VERSION 5.8 ;
BUSBITCHARS "[]" ;
DIVIDERCHAR "/" ;
UNITS
    DATABASE MICRONS 1000 ;
END UNITS

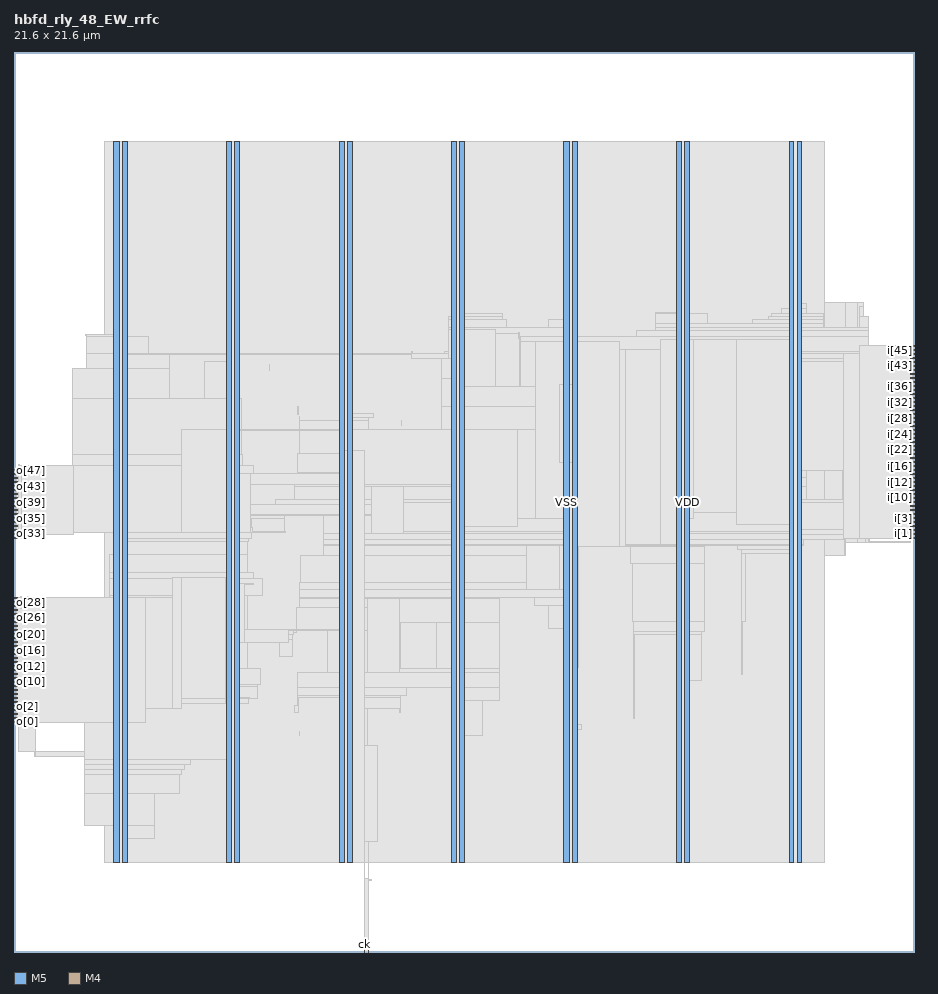
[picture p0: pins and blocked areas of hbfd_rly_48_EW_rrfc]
MACRO hbfd_rly_48_EW_rrfc
  FOREIGN hbfd_rly_48_EW_rrfc 0 0 ;
  CLASS BLOCK ;
  SIZE 21.6 BY 21.6 ;
  PIN ck
    DIRECTION INPUT ;
    USE SIGNAL ;
    PORT
      LAYER M5 ;
        RECT  8.4 0 8.424 0.084 ;
    END
  END ck
  PIN i[0]
    DIRECTION INPUT ;
    USE SIGNAL ;
    PORT
      LAYER M4 ;
        RECT  21.516 9.936 21.6 9.96 ;
    END
  END i[0]
  PIN i[10]
    DIRECTION INPUT ;
    USE SIGNAL ;
    PORT
      LAYER M4 ;
        RECT  21.516 10.896 21.6 10.92 ;
    END
  END i[10]
  PIN i[11]
    DIRECTION INPUT ;
    USE SIGNAL ;
    PORT
      LAYER M4 ;
        RECT  21.516 10.992 21.6 11.016 ;
    END
  END i[11]
  PIN i[12]
    DIRECTION INPUT ;
    USE SIGNAL ;
    PORT
      LAYER M4 ;
        RECT  21.516 11.088 21.6 11.112 ;
    END
  END i[12]
  PIN i[13]
    DIRECTION INPUT ;
    USE SIGNAL ;
    PORT
      LAYER M4 ;
        RECT  21.516 11.184 21.6 11.208 ;
    END
  END i[13]
  PIN i[14]
    DIRECTION INPUT ;
    USE SIGNAL ;
    PORT
      LAYER M4 ;
        RECT  21.516 11.28 21.6 11.304 ;
    END
  END i[14]
  PIN i[15]
    DIRECTION INPUT ;
    USE SIGNAL ;
    PORT
      LAYER M4 ;
        RECT  21.516 11.376 21.6 11.4 ;
    END
  END i[15]
  PIN i[16]
    DIRECTION INPUT ;
    USE SIGNAL ;
    PORT
      LAYER M4 ;
        RECT  21.516 11.472 21.6 11.496 ;
    END
  END i[16]
  PIN i[17]
    DIRECTION INPUT ;
    USE SIGNAL ;
    PORT
      LAYER M4 ;
        RECT  21.516 11.568 21.6 11.592 ;
    END
  END i[17]
  PIN i[18]
    DIRECTION INPUT ;
    USE SIGNAL ;
    PORT
      LAYER M4 ;
        RECT  21.516 11.664 21.6 11.688 ;
    END
  END i[18]
  PIN i[19]
    DIRECTION INPUT ;
    USE SIGNAL ;
    PORT
      LAYER M4 ;
        RECT  21.516 11.76 21.6 11.784 ;
    END
  END i[19]
  PIN i[1]
    DIRECTION INPUT ;
    USE SIGNAL ;
    PORT
      LAYER M4 ;
        RECT  21.516 10.032 21.6 10.056 ;
    END
  END i[1]
  PIN i[20]
    DIRECTION INPUT ;
    USE SIGNAL ;
    PORT
      LAYER M4 ;
        RECT  21.516 11.856 21.6 11.88 ;
    END
  END i[20]
  PIN i[21]
    DIRECTION INPUT ;
    USE SIGNAL ;
    PORT
      LAYER M4 ;
        RECT  21.516 11.952 21.6 11.976 ;
    END
  END i[21]
  PIN i[22]
    DIRECTION INPUT ;
    USE SIGNAL ;
    PORT
      LAYER M4 ;
        RECT  21.516 12.048 21.6 12.072 ;
    END
  END i[22]
  PIN i[23]
    DIRECTION INPUT ;
    USE SIGNAL ;
    PORT
      LAYER M4 ;
        RECT  21.516 12.144 21.6 12.168 ;
    END
  END i[23]
  PIN i[24]
    DIRECTION INPUT ;
    USE SIGNAL ;
    PORT
      LAYER M4 ;
        RECT  21.516 12.24 21.6 12.264 ;
    END
  END i[24]
  PIN i[25]
    DIRECTION INPUT ;
    USE SIGNAL ;
    PORT
      LAYER M4 ;
        RECT  21.516 12.336 21.6 12.36 ;
    END
  END i[25]
  PIN i[26]
    DIRECTION INPUT ;
    USE SIGNAL ;
    PORT
      LAYER M4 ;
        RECT  21.516 12.432 21.6 12.456 ;
    END
  END i[26]
  PIN i[27]
    DIRECTION INPUT ;
    USE SIGNAL ;
    PORT
      LAYER M4 ;
        RECT  21.516 12.528 21.6 12.552 ;
    END
  END i[27]
  PIN i[28]
    DIRECTION INPUT ;
    USE SIGNAL ;
    PORT
      LAYER M4 ;
        RECT  21.516 12.624 21.6 12.648 ;
    END
  END i[28]
  PIN i[29]
    DIRECTION INPUT ;
    USE SIGNAL ;
    PORT
      LAYER M4 ;
        RECT  21.516 12.72 21.6 12.744 ;
    END
  END i[29]
  PIN i[2]
    DIRECTION INPUT ;
    USE SIGNAL ;
    PORT
      LAYER M4 ;
        RECT  21.516 10.128 21.6 10.152 ;
    END
  END i[2]
  PIN i[30]
    DIRECTION INPUT ;
    USE SIGNAL ;
    PORT
      LAYER M4 ;
        RECT  21.516 12.816 21.6 12.84 ;
    END
  END i[30]
  PIN i[31]
    DIRECTION INPUT ;
    USE SIGNAL ;
    PORT
      LAYER M4 ;
        RECT  21.516 12.912 21.6 12.936 ;
    END
  END i[31]
  PIN i[32]
    DIRECTION INPUT ;
    USE SIGNAL ;
    PORT
      LAYER M4 ;
        RECT  21.516 13.008 21.6 13.032 ;
    END
  END i[32]
  PIN i[33]
    DIRECTION INPUT ;
    USE SIGNAL ;
    PORT
      LAYER M4 ;
        RECT  21.516 13.104 21.6 13.128 ;
    END
  END i[33]
  PIN i[34]
    DIRECTION INPUT ;
    USE SIGNAL ;
    PORT
      LAYER M4 ;
        RECT  21.516 13.2 21.6 13.224 ;
    END
  END i[34]
  PIN i[35]
    DIRECTION INPUT ;
    USE SIGNAL ;
    PORT
      LAYER M4 ;
        RECT  21.516 13.296 21.6 13.32 ;
    END
  END i[35]
  PIN i[36]
    DIRECTION INPUT ;
    USE SIGNAL ;
    PORT
      LAYER M4 ;
        RECT  21.516 13.392 21.6 13.416 ;
    END
  END i[36]
  PIN i[37]
    DIRECTION INPUT ;
    USE SIGNAL ;
    PORT
      LAYER M4 ;
        RECT  21.516 13.488 21.6 13.512 ;
    END
  END i[37]
  PIN i[38]
    DIRECTION INPUT ;
    USE SIGNAL ;
    PORT
      LAYER M4 ;
        RECT  21.516 13.584 21.6 13.608 ;
    END
  END i[38]
  PIN i[39]
    DIRECTION INPUT ;
    USE SIGNAL ;
    PORT
      LAYER M4 ;
        RECT  21.516 13.68 21.6 13.704 ;
    END
  END i[39]
  PIN i[3]
    DIRECTION INPUT ;
    USE SIGNAL ;
    PORT
      LAYER M4 ;
        RECT  21.516 10.224 21.6 10.248 ;
    END
  END i[3]
  PIN i[40]
    DIRECTION INPUT ;
    USE SIGNAL ;
    PORT
      LAYER M4 ;
        RECT  21.516 13.776 21.6 13.8 ;
    END
  END i[40]
  PIN i[41]
    DIRECTION INPUT ;
    USE SIGNAL ;
    PORT
      LAYER M4 ;
        RECT  21.516 13.872 21.6 13.896 ;
    END
  END i[41]
  PIN i[42]
    DIRECTION INPUT ;
    USE SIGNAL ;
    PORT
      LAYER M4 ;
        RECT  21.516 13.968 21.6 13.992 ;
    END
  END i[42]
  PIN i[43]
    DIRECTION INPUT ;
    USE SIGNAL ;
    PORT
      LAYER M4 ;
        RECT  21.516 14.064 21.6 14.088 ;
    END
  END i[43]
  PIN i[44]
    DIRECTION INPUT ;
    USE SIGNAL ;
    PORT
      LAYER M4 ;
        RECT  21.516 14.16 21.6 14.184 ;
    END
  END i[44]
  PIN i[45]
    DIRECTION INPUT ;
    USE SIGNAL ;
    PORT
      LAYER M4 ;
        RECT  21.516 14.256 21.6 14.28 ;
    END
  END i[45]
  PIN i[46]
    DIRECTION INPUT ;
    USE SIGNAL ;
    PORT
      LAYER M4 ;
        RECT  21.516 14.352 21.6 14.376 ;
    END
  END i[46]
  PIN i[47]
    DIRECTION INPUT ;
    USE SIGNAL ;
    PORT
      LAYER M4 ;
        RECT  21.516 14.448 21.6 14.472 ;
    END
  END i[47]
  PIN i[4]
    DIRECTION INPUT ;
    USE SIGNAL ;
    PORT
      LAYER M4 ;
        RECT  21.516 10.32 21.6 10.344 ;
    END
  END i[4]
  PIN i[5]
    DIRECTION INPUT ;
    USE SIGNAL ;
    PORT
      LAYER M4 ;
        RECT  21.516 10.416 21.6 10.44 ;
    END
  END i[5]
  PIN i[6]
    DIRECTION INPUT ;
    USE SIGNAL ;
    PORT
      LAYER M4 ;
        RECT  21.516 10.512 21.6 10.536 ;
    END
  END i[6]
  PIN i[7]
    DIRECTION INPUT ;
    USE SIGNAL ;
    PORT
      LAYER M4 ;
        RECT  21.516 10.608 21.6 10.632 ;
    END
  END i[7]
  PIN i[8]
    DIRECTION INPUT ;
    USE SIGNAL ;
    PORT
      LAYER M4 ;
        RECT  21.516 10.704 21.6 10.728 ;
    END
  END i[8]
  PIN i[9]
    DIRECTION INPUT ;
    USE SIGNAL ;
    PORT
      LAYER M4 ;
        RECT  21.516 10.8 21.6 10.824 ;
    END
  END i[9]
  PIN o[0]
    DIRECTION OUTPUT ;
    USE SIGNAL ;
    PORT
      LAYER M4 ;
        RECT  0 5.52 0.084 5.544 ;
    END
  END o[0]
  PIN o[10]
    DIRECTION OUTPUT ;
    USE SIGNAL ;
    PORT
      LAYER M4 ;
        RECT  0 6.48 0.084 6.504 ;
    END
  END o[10]
  PIN o[11]
    DIRECTION OUTPUT ;
    USE SIGNAL ;
    PORT
      LAYER M4 ;
        RECT  0 6.576 0.084 6.6 ;
    END
  END o[11]
  PIN o[12]
    DIRECTION OUTPUT ;
    USE SIGNAL ;
    PORT
      LAYER M4 ;
        RECT  0 6.672 0.084 6.696 ;
    END
  END o[12]
  PIN o[13]
    DIRECTION OUTPUT ;
    USE SIGNAL ;
    PORT
      LAYER M4 ;
        RECT  0 6.768 0.084 6.792 ;
    END
  END o[13]
  PIN o[14]
    DIRECTION OUTPUT ;
    USE SIGNAL ;
    PORT
      LAYER M4 ;
        RECT  0 6.864 0.084 6.888 ;
    END
  END o[14]
  PIN o[15]
    DIRECTION OUTPUT ;
    USE SIGNAL ;
    PORT
      LAYER M4 ;
        RECT  0 6.96 0.084 6.984 ;
    END
  END o[15]
  PIN o[16]
    DIRECTION OUTPUT ;
    USE SIGNAL ;
    PORT
      LAYER M4 ;
        RECT  0 7.056 0.084 7.08 ;
    END
  END o[16]
  PIN o[17]
    DIRECTION OUTPUT ;
    USE SIGNAL ;
    PORT
      LAYER M4 ;
        RECT  0 7.152 0.084 7.176 ;
    END
  END o[17]
  PIN o[18]
    DIRECTION OUTPUT ;
    USE SIGNAL ;
    PORT
      LAYER M4 ;
        RECT  0 7.248 0.084 7.272 ;
    END
  END o[18]
  PIN o[19]
    DIRECTION OUTPUT ;
    USE SIGNAL ;
    PORT
      LAYER M4 ;
        RECT  0 7.344 0.084 7.368 ;
    END
  END o[19]
  PIN o[1]
    DIRECTION OUTPUT ;
    USE SIGNAL ;
    PORT
      LAYER M4 ;
        RECT  0 5.616 0.084 5.64 ;
    END
  END o[1]
  PIN o[20]
    DIRECTION OUTPUT ;
    USE SIGNAL ;
    PORT
      LAYER M4 ;
        RECT  0 7.44 0.084 7.464 ;
    END
  END o[20]
  PIN o[21]
    DIRECTION OUTPUT ;
    USE SIGNAL ;
    PORT
      LAYER M4 ;
        RECT  0 7.536 0.084 7.56 ;
    END
  END o[21]
  PIN o[22]
    DIRECTION OUTPUT ;
    USE SIGNAL ;
    PORT
      LAYER M4 ;
        RECT  0 7.632 0.084 7.656 ;
    END
  END o[22]
  PIN o[23]
    DIRECTION OUTPUT ;
    USE SIGNAL ;
    PORT
      LAYER M4 ;
        RECT  0 7.728 0.084 7.752 ;
    END
  END o[23]
  PIN o[24]
    DIRECTION OUTPUT ;
    USE SIGNAL ;
    PORT
      LAYER M4 ;
        RECT  0 7.824 0.084 7.848 ;
    END
  END o[24]
  PIN o[25]
    DIRECTION OUTPUT ;
    USE SIGNAL ;
    PORT
      LAYER M4 ;
        RECT  0 7.92 0.084 7.944 ;
    END
  END o[25]
  PIN o[26]
    DIRECTION OUTPUT ;
    USE SIGNAL ;
    PORT
      LAYER M4 ;
        RECT  0 8.016 0.084 8.04 ;
    END
  END o[26]
  PIN o[27]
    DIRECTION OUTPUT ;
    USE SIGNAL ;
    PORT
      LAYER M4 ;
        RECT  0 8.112 0.084 8.136 ;
    END
  END o[27]
  PIN o[28]
    DIRECTION OUTPUT ;
    USE SIGNAL ;
    PORT
      LAYER M4 ;
        RECT  0 8.208 0.084 8.232 ;
    END
  END o[28]
  PIN o[29]
    DIRECTION OUTPUT ;
    USE SIGNAL ;
    PORT
      LAYER M4 ;
        RECT  0 8.304 0.084 8.328 ;
    END
  END o[29]
  PIN o[2]
    DIRECTION OUTPUT ;
    USE SIGNAL ;
    PORT
      LAYER M4 ;
        RECT  0 5.712 0.084 5.736 ;
    END
  END o[2]
  PIN o[30]
    DIRECTION OUTPUT ;
    USE SIGNAL ;
    PORT
      LAYER M4 ;
        RECT  0 8.4 0.084 8.424 ;
    END
  END o[30]
  PIN o[31]
    DIRECTION OUTPUT ;
    USE SIGNAL ;
    PORT
      LAYER M4 ;
        RECT  0 8.496 0.084 8.52 ;
    END
  END o[31]
  PIN o[32]
    DIRECTION OUTPUT ;
    USE SIGNAL ;
    PORT
      LAYER M4 ;
        RECT  0 9.936 0.084 9.96 ;
    END
  END o[32]
  PIN o[33]
    DIRECTION OUTPUT ;
    USE SIGNAL ;
    PORT
      LAYER M4 ;
        RECT  0 10.032 0.084 10.056 ;
    END
  END o[33]
  PIN o[34]
    DIRECTION OUTPUT ;
    USE SIGNAL ;
    PORT
      LAYER M4 ;
        RECT  0 10.128 0.084 10.152 ;
    END
  END o[34]
  PIN o[35]
    DIRECTION OUTPUT ;
    USE SIGNAL ;
    PORT
      LAYER M4 ;
        RECT  0 10.224 0.084 10.248 ;
    END
  END o[35]
  PIN o[36]
    DIRECTION OUTPUT ;
    USE SIGNAL ;
    PORT
      LAYER M4 ;
        RECT  0 10.32 0.084 10.344 ;
    END
  END o[36]
  PIN o[37]
    DIRECTION OUTPUT ;
    USE SIGNAL ;
    PORT
      LAYER M4 ;
        RECT  0 10.416 0.084 10.44 ;
    END
  END o[37]
  PIN o[38]
    DIRECTION OUTPUT ;
    USE SIGNAL ;
    PORT
      LAYER M4 ;
        RECT  0 10.512 0.084 10.536 ;
    END
  END o[38]
  PIN o[39]
    DIRECTION OUTPUT ;
    USE SIGNAL ;
    PORT
      LAYER M4 ;
        RECT  0 10.608 0.084 10.632 ;
    END
  END o[39]
  PIN o[3]
    DIRECTION OUTPUT ;
    USE SIGNAL ;
    PORT
      LAYER M4 ;
        RECT  0 5.808 0.084 5.832 ;
    END
  END o[3]
  PIN o[40]
    DIRECTION OUTPUT ;
    USE SIGNAL ;
    PORT
      LAYER M4 ;
        RECT  0 10.704 0.084 10.728 ;
    END
  END o[40]
  PIN o[41]
    DIRECTION OUTPUT ;
    USE SIGNAL ;
    PORT
      LAYER M4 ;
        RECT  0 10.8 0.084 10.824 ;
    END
  END o[41]
  PIN o[42]
    DIRECTION OUTPUT ;
    USE SIGNAL ;
    PORT
      LAYER M4 ;
        RECT  0 10.896 0.084 10.92 ;
    END
  END o[42]
  PIN o[43]
    DIRECTION OUTPUT ;
    USE SIGNAL ;
    PORT
      LAYER M4 ;
        RECT  0 10.992 0.084 11.016 ;
    END
  END o[43]
  PIN o[44]
    DIRECTION OUTPUT ;
    USE SIGNAL ;
    PORT
      LAYER M4 ;
        RECT  0 11.088 0.084 11.112 ;
    END
  END o[44]
  PIN o[45]
    DIRECTION OUTPUT ;
    USE SIGNAL ;
    PORT
      LAYER M4 ;
        RECT  0 11.184 0.084 11.208 ;
    END
  END o[45]
  PIN o[46]
    DIRECTION OUTPUT ;
    USE SIGNAL ;
    PORT
      LAYER M4 ;
        RECT  0 11.28 0.084 11.304 ;
    END
  END o[46]
  PIN o[47]
    DIRECTION OUTPUT ;
    USE SIGNAL ;
    PORT
      LAYER M4 ;
        RECT  0 11.376 0.084 11.4 ;
    END
  END o[47]
  PIN o[4]
    DIRECTION OUTPUT ;
    USE SIGNAL ;
    PORT
      LAYER M4 ;
        RECT  0 5.904 0.084 5.928 ;
    END
  END o[4]
  PIN o[5]
    DIRECTION OUTPUT ;
    USE SIGNAL ;
    PORT
      LAYER M4 ;
        RECT  0 6 0.084 6.024 ;
    END
  END o[5]
  PIN o[6]
    DIRECTION OUTPUT ;
    USE SIGNAL ;
    PORT
      LAYER M4 ;
        RECT  0 6.096 0.084 6.12 ;
    END
  END o[6]
  PIN o[7]
    DIRECTION OUTPUT ;
    USE SIGNAL ;
    PORT
      LAYER M4 ;
        RECT  0 6.192 0.084 6.216 ;
    END
  END o[7]
  PIN o[8]
    DIRECTION OUTPUT ;
    USE SIGNAL ;
    PORT
      LAYER M4 ;
        RECT  0 6.288 0.084 6.312 ;
    END
  END o[8]
  PIN o[9]
    DIRECTION OUTPUT ;
    USE SIGNAL ;
    PORT
      LAYER M4 ;
        RECT  0 6.384 0.084 6.408 ;
    END
  END o[9]
  PIN rfi
    DIRECTION INPUT ;
    USE SIGNAL ;
    PORT
      LAYER M4 ;
        RECT  21.516 14.544 21.6 14.568 ;
    END
  END rfi
  PIN rfo
    DIRECTION OUTPUT ;
    USE SIGNAL ;
    PORT
      LAYER M4 ;
        RECT  0 11.472 0.084 11.496 ;
    END
  END rfo
  PIN rs
    DIRECTION INPUT ;
    USE SIGNAL ;
    PORT
      LAYER M5 ;
        RECT  8.496 0 8.52 0.084 ;
    END
  END rs
  PIN rso
    DIRECTION OUTPUT ;
    USE SIGNAL ;
    PORT
      LAYER M4 ;
        RECT  0 11.568 0.084 11.592 ;
    END
  END rso
  PIN VDD
    DIRECTION INOUT ;
    USE POWER ;
    PORT
      LAYER M5 ;
        RECT  18.792 2.151 18.912 19.449 ;
        RECT  16.092 2.151 16.212 19.449 ;
        RECT  13.392 2.151 13.512 19.449 ;
        RECT  10.692 2.151 10.812 19.449 ;
        RECT  7.992 2.151 8.112 19.449 ;
        RECT  5.292 2.151 5.412 19.449 ;
        RECT  2.592 2.151 2.712 19.449 ;
    END
  END VDD
  PIN VSS
    DIRECTION INOUT ;
    USE GROUND ;
    PORT
      LAYER M5 ;
        RECT  18.6 2.137 18.72 19.463 ;
        RECT  15.9 2.137 16.02 19.463 ;
        RECT  13.2 2.137 13.32 19.463 ;
        RECT  10.5 2.137 10.62 19.463 ;
        RECT  7.8 2.137 7.92 19.463 ;
        RECT  5.1 2.137 5.22 19.463 ;
        RECT  2.4 2.137 2.52 19.463 ;
    END
  END VSS
  OBS
    LAYER RVTN ;
     RECT  2.16 2.16 19.44 2.295 ;
     RECT  2.16 2.565 19.44 2.835 ;
     RECT  2.16 3.105 19.44 3.375 ;
     RECT  2.16 3.645 19.44 3.915 ;
     RECT  2.16 4.185 19.44 4.455 ;
     RECT  2.16 4.725 19.44 4.995 ;
     RECT  2.16 5.265 19.44 5.535 ;
     RECT  2.16 5.805 19.44 6.075 ;
     RECT  2.16 6.345 19.44 6.615 ;
     RECT  2.16 6.885 19.44 7.155 ;
     RECT  2.16 7.425 19.44 7.695 ;
     RECT  2.16 7.965 19.44 8.235 ;
     RECT  2.16 8.505 19.44 8.775 ;
     RECT  2.16 9.045 19.44 9.315 ;
     RECT  2.16 9.585 19.44 9.855 ;
     RECT  2.16 10.125 19.44 10.395 ;
     RECT  2.16 10.665 19.44 10.935 ;
     RECT  2.16 11.205 19.44 11.475 ;
     RECT  2.16 11.745 19.44 12.015 ;
     RECT  2.16 12.285 19.44 12.555 ;
     RECT  2.16 12.825 19.44 13.095 ;
     RECT  2.16 13.365 19.44 13.635 ;
     RECT  2.16 13.905 19.44 14.175 ;
     RECT  2.16 14.445 19.44 14.715 ;
     RECT  2.16 14.985 19.44 15.255 ;
     RECT  2.16 15.525 19.44 15.795 ;
     RECT  2.16 16.065 19.44 16.335 ;
     RECT  2.16 16.605 19.44 16.875 ;
     RECT  2.16 17.145 19.44 17.415 ;
     RECT  2.16 17.685 19.44 17.955 ;
     RECT  2.16 18.225 19.44 18.495 ;
     RECT  2.16 18.765 19.44 19.035 ;
     RECT  2.16 19.305 19.44 19.44 ;
    LAYER RVTP ;
     RECT  2.16 2.295 19.44 2.565 ;
     RECT  2.16 2.835 19.44 3.105 ;
     RECT  2.16 3.375 19.44 3.645 ;
     RECT  2.16 3.915 19.44 4.185 ;
     RECT  2.16 4.455 19.44 4.725 ;
     RECT  2.16 4.995 19.44 5.265 ;
     RECT  2.16 5.535 19.44 5.805 ;
     RECT  2.16 6.075 19.44 6.345 ;
     RECT  2.16 6.615 19.44 6.885 ;
     RECT  2.16 7.155 19.44 7.425 ;
     RECT  2.16 7.695 19.44 7.965 ;
     RECT  2.16 8.235 19.44 8.505 ;
     RECT  2.16 8.775 19.44 9.045 ;
     RECT  2.16 9.315 19.44 9.585 ;
     RECT  2.16 9.855 19.44 10.125 ;
     RECT  2.16 10.395 19.44 10.665 ;
     RECT  2.16 10.935 19.44 11.205 ;
     RECT  2.16 11.475 19.44 11.745 ;
     RECT  2.16 12.015 19.44 12.285 ;
     RECT  2.16 12.555 19.44 12.825 ;
     RECT  2.16 13.095 19.44 13.365 ;
     RECT  2.16 13.635 19.44 13.905 ;
     RECT  2.16 14.175 19.44 14.445 ;
     RECT  2.16 14.715 19.44 14.985 ;
     RECT  2.16 15.255 19.44 15.525 ;
     RECT  2.16 15.795 19.44 16.065 ;
     RECT  2.16 16.335 19.44 16.605 ;
     RECT  2.16 16.875 19.44 17.145 ;
     RECT  2.16 17.415 19.44 17.685 ;
     RECT  2.16 17.955 19.44 18.225 ;
     RECT  2.16 18.495 19.44 18.765 ;
     RECT  2.16 19.035 19.44 19.305 ;
    LAYER M1 ;
     RECT  2.16 2.151 19.44 19.449 ;
    LAYER M2 ;
     RECT  0.103 6.354 0.139 6.372 ;
     RECT  0.103 8.01 0.203 8.028 ;
     RECT  0.103 10.134 0.203 10.854 ;
     RECT  0.139 5.886 0.239 6.372 ;
     RECT  0.103 4.806 0.499 4.824 ;
     RECT  0.239 5.886 0.535 6.102 ;
     RECT  1.399 13.986 2.011 14.004 ;
     RECT  1.687 3.042 2.16 3.06 ;
     RECT  0.499 4.698 2.16 4.824 ;
     RECT  0.535 5.58 2.16 6.102 ;
     RECT  2.011 13.446 2.16 14.004 ;
     RECT  1.723 14.796 2.16 14.814 ;
     RECT  2.16 2.151 19.44 19.449 ;
     RECT  19.44 9.522 19.967 15.588 ;
     RECT  19.967 9.828 20.255 15.588 ;
     RECT  20.255 14.148 20.399 15.588 ;
     RECT  20.255 9.828 20.435 13.356 ;
     RECT  20.399 14.418 20.435 15.246 ;
     RECT  20.435 14.76 20.471 15.246 ;
     RECT  20.435 9.828 20.507 13.158 ;
     RECT  20.471 15.228 20.507 15.246 ;
     RECT  20.507 9.828 20.543 10.116 ;
     RECT  20.507 11.016 20.759 11.034 ;
     RECT  20.507 12.636 21.415 13.158 ;
     RECT  21.415 12.636 21.479 13.509 ;
     RECT  20.543 9.828 21.515 9.846 ;
     RECT  21.479 12.798 21.515 13.509 ;
    LAYER M3 ;
     RECT  8.496 1.723 8.514 2.143 ;
     RECT  2.415 2.143 2.505 2.413 ;
     RECT  5.115 2.143 5.205 2.413 ;
     RECT  10.515 2.143 10.605 2.413 ;
     RECT  13.215 2.143 13.305 2.413 ;
     RECT  15.915 2.143 16.005 2.413 ;
     RECT  18.615 2.143 18.705 2.413 ;
     RECT  7.815 2.143 8.514 2.641 ;
     RECT  2.415 2.413 2.697 2.731 ;
     RECT  2.415 2.731 3.366 3.037 ;
     RECT  1.692 3.037 3.366 3.811 ;
     RECT  1.692 3.811 3.978 4.261 ;
     RECT  1.692 4.261 4.014 4.387 ;
     RECT  1.692 4.387 4.086 4.495 ;
     RECT  1.692 4.495 4.23 4.621 ;
     RECT  5.115 2.413 5.397 4.621 ;
     RECT  0.504 4.693 0.522 4.801 ;
     RECT  7.815 2.641 8.73 4.955 ;
     RECT  10.515 2.413 10.797 5.197 ;
     RECT  6.84 5.197 6.858 5.297 ;
     RECT  13.215 2.413 13.497 5.341 ;
     RECT  13.215 5.341 13.626 5.459 ;
     RECT  0.108 4.801 0.522 5.575 ;
     RECT  7.815 4.955 8.478 5.845 ;
     RECT  9.252 5.737 9.27 5.845 ;
     RECT  6.732 5.737 6.822 5.909 ;
     RECT  1.692 4.621 5.397 5.971 ;
     RECT  10.515 5.197 11.25 6.043 ;
     RECT  1.692 5.971 5.634 6.079 ;
     RECT  6.804 5.909 6.822 6.115 ;
     RECT  7.815 5.845 9.27 6.115 ;
     RECT  6.804 6.115 9.27 6.151 ;
     RECT  6.804 6.151 9.414 6.349 ;
     RECT  10.515 6.043 11.646 6.349 ;
     RECT  1.692 6.079 5.85 6.365 ;
     RECT  0.108 5.575 0.558 6.413 ;
     RECT  2.304 6.365 5.85 6.421 ;
     RECT  15.915 2.413 16.197 6.511 ;
     RECT  6.804 6.349 11.646 6.719 ;
     RECT  0.144 6.413 0.558 6.797 ;
     RECT  2.304 6.421 5.922 6.809 ;
     RECT  9.252 6.719 11.646 6.809 ;
     RECT  13.215 5.459 13.497 6.817 ;
     RECT  0.144 6.797 0.522 7.277 ;
     RECT  6.372 7.087 6.678 7.502 ;
     RECT  6.408 7.502 6.678 7.619 ;
     RECT  14.868 5.611 14.886 7.627 ;
     RECT  15.915 6.511 16.506 7.627 ;
     RECT  6.696 7.627 6.714 7.663 ;
     RECT  14.868 7.627 16.506 7.699 ;
     RECT  6.696 7.663 6.786 7.723 ;
     RECT  7.524 6.719 8.478 7.723 ;
     RECT  6.696 7.723 8.478 7.727 ;
     RECT  13.215 6.817 13.554 7.771 ;
     RECT  9.252 6.809 9.27 7.897 ;
     RECT  10.152 6.809 11.646 7.897 ;
     RECT  14.868 7.699 16.578 7.933 ;
     RECT  17.46 6.655 17.478 7.933 ;
     RECT  0.144 7.277 0.198 7.996 ;
     RECT  0.108 7.996 0.198 8.141 ;
     RECT  0.18 8.141 0.198 8.189 ;
     RECT  6.768 7.727 8.478 8.267 ;
     RECT  12.816 7.771 13.554 8.311 ;
     RECT  6.84 8.267 8.478 8.473 ;
     RECT  9.252 7.897 11.646 8.473 ;
     RECT  6.84 8.473 11.646 8.509 ;
     RECT  12.492 8.311 13.554 8.509 ;
     RECT  0.324 8.395 0.342 8.525 ;
     RECT  2.304 6.809 5.598 8.545 ;
     RECT  6.84 8.509 13.554 8.699 ;
     RECT  6.84 8.699 12.294 8.879 ;
     RECT  2.304 8.545 5.958 8.969 ;
     RECT  2.304 8.969 5.742 9.113 ;
     RECT  14.832 7.933 16.578 9.319 ;
     RECT  6.876 8.879 12.294 9.509 ;
     RECT  2.304 9.113 5.598 9.545 ;
     RECT  17.46 7.933 17.55 9.553 ;
     RECT  18.615 2.413 18.897 9.553 ;
     RECT  17.46 9.553 18.897 9.661 ;
     RECT  14.796 9.319 16.578 9.739 ;
     RECT  7.416 9.509 12.294 9.751 ;
     RECT  13.104 8.699 13.554 9.751 ;
     RECT  14.292 9.739 16.578 9.751 ;
     RECT  17.352 9.661 18.897 9.751 ;
     RECT  7.416 9.751 13.554 9.781 ;
     RECT  14.292 9.751 18.954 9.781 ;
     RECT  2.415 9.545 5.598 9.859 ;
     RECT  7.416 9.781 18.954 9.895 ;
     RECT  19.944 9.517 19.962 9.895 ;
     RECT  2.415 9.859 5.634 9.931 ;
     RECT  7.416 9.895 19.962 10.049 ;
     RECT  9.36 10.049 19.962 10.093 ;
     RECT  0.144 9.931 0.162 10.129 ;
     RECT  2.415 9.931 5.706 10.291 ;
     RECT  2.376 10.291 5.706 10.399 ;
     RECT  6.48 10.075 6.498 10.399 ;
     RECT  2.376 10.399 6.498 10.471 ;
     RECT  7.416 10.049 8.586 10.471 ;
     RECT  1.404 10.027 1.422 10.507 ;
     RECT  2.304 10.471 8.586 10.507 ;
     RECT  21.492 9.823 21.51 10.541 ;
     RECT  1.404 10.507 8.586 10.733 ;
     RECT  9.36 10.093 20.538 10.795 ;
     RECT  6.264 10.733 8.586 10.859 ;
     RECT  9.36 10.795 20.754 10.859 ;
     RECT  19.872 10.859 20.754 11.039 ;
     RECT  0.108 10.129 0.198 11.165 ;
     RECT  6.732 10.859 8.586 11.173 ;
     RECT  9.36 10.859 19.026 11.173 ;
     RECT  6.732 11.173 19.026 11.399 ;
     RECT  0.108 11.165 0.162 11.405 ;
     RECT  6.732 11.399 8.586 11.405 ;
     RECT  1.404 10.733 5.454 11.479 ;
     RECT  6.804 11.405 8.586 11.507 ;
     RECT  1.404 11.479 5.742 11.669 ;
     RECT  0.108 11.405 0.126 11.693 ;
     RECT  9.396 11.399 19.026 11.755 ;
     RECT  9.396 11.755 19.098 11.911 ;
     RECT  19.872 11.039 20.502 11.911 ;
     RECT  1.404 11.669 5.49 11.939 ;
     RECT  6.804 11.507 8.514 11.975 ;
     RECT  9.396 11.911 20.502 12.083 ;
     RECT  9.396 12.083 18.918 12.283 ;
     RECT  9.36 12.283 18.918 12.479 ;
     RECT  21.42 12.235 21.438 12.523 ;
     RECT  19.836 12.083 20.502 12.551 ;
     RECT  6.84 11.975 8.514 12.749 ;
     RECT  9.288 12.631 9.306 12.749 ;
     RECT  7.815 12.749 8.514 12.829 ;
     RECT  6.84 12.749 6.858 12.857 ;
     RECT  7.815 12.829 8.622 12.929 ;
     RECT  6.804 12.901 6.822 13.091 ;
     RECT  10.26 12.479 18.918 13.099 ;
     RECT  19.836 12.551 20.43 13.099 ;
     RECT  1.404 11.939 5.454 13.289 ;
     RECT  21.42 12.523 21.51 13.514 ;
     RECT  21.492 13.514 21.51 13.517 ;
     RECT  10.26 13.099 20.43 13.771 ;
     RECT  1.404 13.289 3.726 14.009 ;
     RECT  6.12 13.945 6.138 14.099 ;
     RECT  4.572 13.289 5.397 14.171 ;
     RECT  10.26 13.771 20.502 14.251 ;
     RECT  1.728 14.009 3.726 14.369 ;
     RECT  9.54 14.251 20.502 14.369 ;
     RECT  9.54 14.369 9.558 14.405 ;
     RECT  10.332 14.369 20.502 14.405 ;
     RECT  1.728 14.369 3.222 14.783 ;
     RECT  10.44 14.405 20.502 14.783 ;
     RECT  1.728 14.783 2.697 14.819 ;
     RECT  14.94 14.783 20.502 14.909 ;
     RECT  10.44 14.783 13.497 14.981 ;
     RECT  15.408 14.909 20.502 14.981 ;
     RECT  15.408 14.981 19.422 15.089 ;
     RECT  10.44 14.981 11.826 15.179 ;
     RECT  12.816 14.981 13.497 15.179 ;
     RECT  17.712 15.089 19.422 15.179 ;
     RECT  10.44 15.179 11.718 15.251 ;
     RECT  18.108 15.179 19.422 15.251 ;
     RECT  20.304 14.981 20.502 15.251 ;
     RECT  10.515 15.251 11.718 15.323 ;
     RECT  15.408 15.089 16.65 15.323 ;
     RECT  18.18 15.251 19.422 15.323 ;
     RECT  15.408 15.323 16.197 15.359 ;
     RECT  18.432 15.323 19.026 15.449 ;
     RECT  20.304 15.251 20.394 15.485 ;
     RECT  18.615 15.449 19.026 15.557 ;
     RECT  20.376 15.485 20.394 15.593 ;
     RECT  2.415 14.819 2.697 19.187 ;
     RECT  5.115 14.171 5.397 19.187 ;
     RECT  7.815 12.929 8.097 19.187 ;
     RECT  10.515 15.323 10.797 19.187 ;
     RECT  13.215 15.179 13.497 19.187 ;
     RECT  15.915 15.359 16.197 19.187 ;
     RECT  18.615 15.557 18.897 19.187 ;
     RECT  2.415 19.187 2.505 19.457 ;
     RECT  5.115 19.187 5.205 19.457 ;
     RECT  7.815 19.187 7.905 19.457 ;
     RECT  10.515 19.187 10.605 19.457 ;
     RECT  13.215 19.187 13.305 19.457 ;
     RECT  15.915 19.187 16.005 19.457 ;
     RECT  18.615 19.187 18.705 19.457 ;
    LAYER M4 ;
     RECT  0.06 9.936 0.097 11.592 ;
     RECT  0.097 9.936 0.173 11.688 ;
     RECT  0.173 10.032 1.433 11.688 ;
     RECT  0.06 5.52 2.408 8.52 ;
     RECT  1.433 10.08 2.408 11.688 ;
     RECT  2.408 2.148 2.512 19.452 ;
     RECT  2.512 2.418 2.704 19.182 ;
     RECT  2.704 5.52 3.161 8.52 ;
     RECT  3.161 5.856 3.805 8.52 ;
     RECT  2.704 10.08 4.021 11.688 ;
     RECT  3.805 5.856 4.025 9 ;
     RECT  4.025 6.096 5.065 9 ;
     RECT  5.065 6 5.108 9 ;
     RECT  4.021 10.08 5.108 12.552 ;
     RECT  2.704 14.352 5.108 14.376 ;
     RECT  5.108 2.148 5.212 19.452 ;
     RECT  5.212 2.418 5.404 19.182 ;
     RECT  5.404 7.44 5.537 8.856 ;
     RECT  5.404 6.096 5.645 6.12 ;
     RECT  5.404 10.08 5.681 11.496 ;
     RECT  5.681 10.08 5.717 10.2 ;
     RECT  5.537 8.832 5.753 8.856 ;
     RECT  5.717 10.08 6.509 10.104 ;
     RECT  5.537 7.44 6.581 7.752 ;
     RECT  6.581 7.728 7.808 7.752 ;
     RECT  5.681 11.232 7.808 11.496 ;
     RECT  5.404 12.528 7.808 12.552 ;
     RECT  5.404 14.352 7.808 14.376 ;
     RECT  7.808 2.148 7.912 19.452 ;
     RECT  7.912 2.148 8.104 19.182 ;
     RECT  8.485 1.728 8.569 1.752 ;
     RECT  8.104 14.352 9.529 14.376 ;
     RECT  9.529 14.256 10.429 14.376 ;
     RECT  8.104 11.232 10.508 12.552 ;
     RECT  10.429 14.256 10.508 14.952 ;
     RECT  10.508 2.148 10.612 19.452 ;
     RECT  10.612 2.418 10.804 19.182 ;
     RECT  10.804 13.584 11.549 14.952 ;
     RECT  10.804 10.224 12.089 12.552 ;
     RECT  11.549 13.584 12.131 14.856 ;
     RECT  12.131 13.584 12.161 14.76 ;
     RECT  12.089 10.416 12.517 12.552 ;
     RECT  12.161 13.584 12.517 14.664 ;
     RECT  12.517 10.416 13.208 14.664 ;
     RECT  13.208 2.148 13.312 19.452 ;
     RECT  13.312 2.418 13.504 19.182 ;
     RECT  13.504 9.744 14.537 14.664 ;
     RECT  14.537 9.744 14.681 14.472 ;
     RECT  14.681 9.792 15.505 14.472 ;
     RECT  15.505 9.792 15.908 14.712 ;
     RECT  15.908 2.148 16.012 19.452 ;
     RECT  16.012 2.418 16.204 19.182 ;
     RECT  16.204 10.416 16.301 14.712 ;
     RECT  16.301 10.56 17.341 14.712 ;
     RECT  17.341 10.272 18.608 14.712 ;
     RECT  18.608 2.148 18.712 19.452 ;
     RECT  18.712 2.418 18.904 19.182 ;
     RECT  18.904 10.032 19.897 10.152 ;
     RECT  18.904 11.568 19.897 14.184 ;
     RECT  19.897 9.936 20.293 14.376 ;
     RECT  20.293 9.936 21.564 14.568 ;
    LAYER M5 ;
     RECT  8.4 0.016 8.52 1.763 ;
     RECT  8.4 1.763 8.424 2.137 ;
     RECT  2.4 2.137 2.52 2.151 ;
     RECT  5.1 2.137 5.22 2.151 ;
     RECT  10.5 2.137 10.62 2.151 ;
     RECT  13.2 2.137 13.32 2.151 ;
     RECT  15.9 2.137 16.02 2.151 ;
     RECT  18.6 2.137 18.72 2.151 ;
     RECT  0.144 8.245 0.168 8.531 ;
     RECT  13.2 2.151 13.512 11.749 ;
     RECT  7.8 2.137 8.424 12.035 ;
     RECT  13.104 11.749 13.512 13.619 ;
     RECT  12.096 14.725 12.12 14.867 ;
     RECT  2.4 2.151 2.712 19.449 ;
     RECT  5.1 2.151 5.412 19.449 ;
     RECT  7.8 12.035 8.112 19.449 ;
     RECT  10.5 2.151 10.812 19.449 ;
     RECT  13.2 13.619 13.512 19.449 ;
     RECT  15.9 2.151 16.212 19.449 ;
     RECT  18.6 2.151 18.912 19.449 ;
     RECT  2.4 19.449 2.52 19.463 ;
     RECT  5.1 19.449 5.22 19.463 ;
     RECT  7.8 19.449 7.92 19.463 ;
     RECT  10.5 19.449 10.62 19.463 ;
     RECT  13.2 19.449 13.32 19.463 ;
     RECT  15.9 19.449 16.02 19.463 ;
     RECT  18.6 19.449 18.72 19.463 ;
  END
END hbfd_rly_48_EW_rrfc
END LIBRARY
